One B-rep face of a CAD part: STEP entity #1205.
In plain terms, the planar face has unit normal (-1, 0, 0).
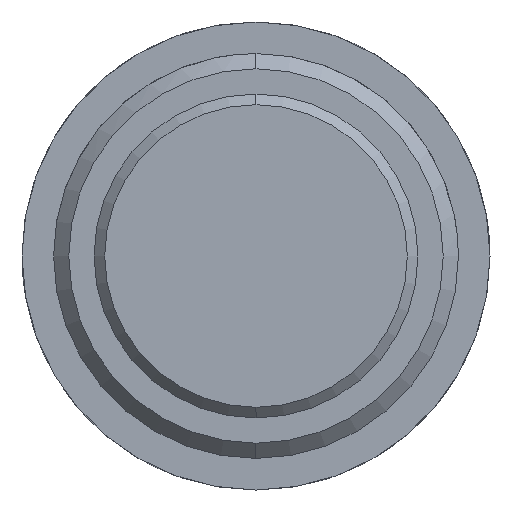
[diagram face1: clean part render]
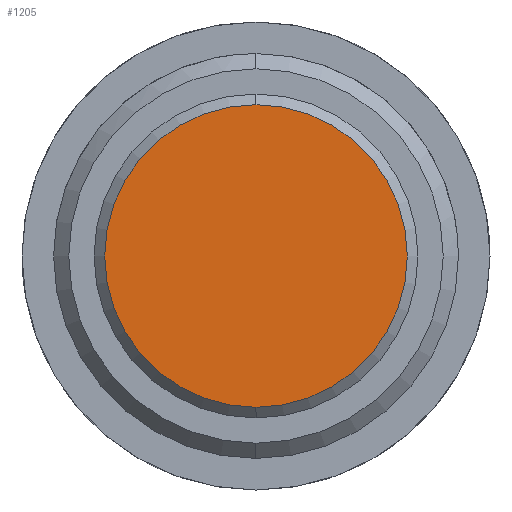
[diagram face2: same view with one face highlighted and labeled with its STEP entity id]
Its self-contained STEP definition (entity closure, numbers rounded to 3 decimals):
#1137=CARTESIAN_POINT('Vertex',(-39.,0.,-23.92)) ;
#1140=CARTESIAN_POINT('Axis2P3D Location',(-39.,0.,0.)) ;
#1144=CARTESIAN_POINT('Vertex',(-39.,23.92,0.)) ;
#1147=CARTESIAN_POINT('Axis2P3D Location',(-39.,0.,0.)) ;
#1151=CARTESIAN_POINT('Vertex',(-39.,0.,23.92)) ;
#1173=CARTESIAN_POINT('Axis2P3D Location',(-39.,0.,0.)) ;
#1177=CARTESIAN_POINT('Vertex',(-39.,-23.92,0.)) ;
#1180=CARTESIAN_POINT('Axis2P3D Location',(-39.,0.,0.)) ;
#1194=CARTESIAN_POINT('Axis2P3D Location',(-39.,0.,0.)) ;
#1141=DIRECTION('Axis2P3D Direction',(1.,0.,-0.)) ;
#1148=DIRECTION('Axis2P3D Direction',(1.,0.,-0.)) ;
#1174=DIRECTION('Axis2P3D Direction',(1.,0.,-0.)) ;
#1181=DIRECTION('Axis2P3D Direction',(1.,0.,-0.)) ;
#1195=DIRECTION('Axis2P3D Direction',(1.,0.,-0.)) ;
#1196=DIRECTION('Axis2P3D XDirection',(-0.,0.,-1.)) ;
#1142=AXIS2_PLACEMENT_3D('Circle Axis2P3D',#1140,#1141,$) ;
#1149=AXIS2_PLACEMENT_3D('Circle Axis2P3D',#1147,#1148,$) ;
#1175=AXIS2_PLACEMENT_3D('Circle Axis2P3D',#1173,#1174,$) ;
#1182=AXIS2_PLACEMENT_3D('Circle Axis2P3D',#1180,#1181,$) ;
#1197=AXIS2_PLACEMENT_3D('Plane Axis2P3D',#1194,#1195,#1196) ;
#1200=ORIENTED_EDGE('',*,*,#1146,.F.) ;
#1201=ORIENTED_EDGE('',*,*,#1184,.F.) ;
#1202=ORIENTED_EDGE('',*,*,#1179,.F.) ;
#1203=ORIENTED_EDGE('',*,*,#1153,.F.) ;
#1205=ADVANCED_FACE('AGS3422M27',(#1204),#1198,.F.) ;
#1143=CIRCLE('generated circle',#1142,23.92) ;
#1150=CIRCLE('generated circle',#1149,23.92) ;
#1176=CIRCLE('generated circle',#1175,23.92) ;
#1183=CIRCLE('generated circle',#1182,23.92) ;
#1146=EDGE_CURVE('',#1138,#1145,#1143,.T.) ;
#1153=EDGE_CURVE('',#1145,#1152,#1150,.T.) ;
#1179=EDGE_CURVE('',#1152,#1178,#1176,.T.) ;
#1184=EDGE_CURVE('',#1178,#1138,#1183,.T.) ;
#1199=EDGE_LOOP('',(#1200,#1201,#1202,#1203)) ;
#1204=FACE_OUTER_BOUND('',#1199,.T.) ;
#1198=PLANE('Plane',#1197) ;
#1138=VERTEX_POINT('',#1137) ;
#1145=VERTEX_POINT('',#1144) ;
#1152=VERTEX_POINT('',#1151) ;
#1178=VERTEX_POINT('',#1177) ;
